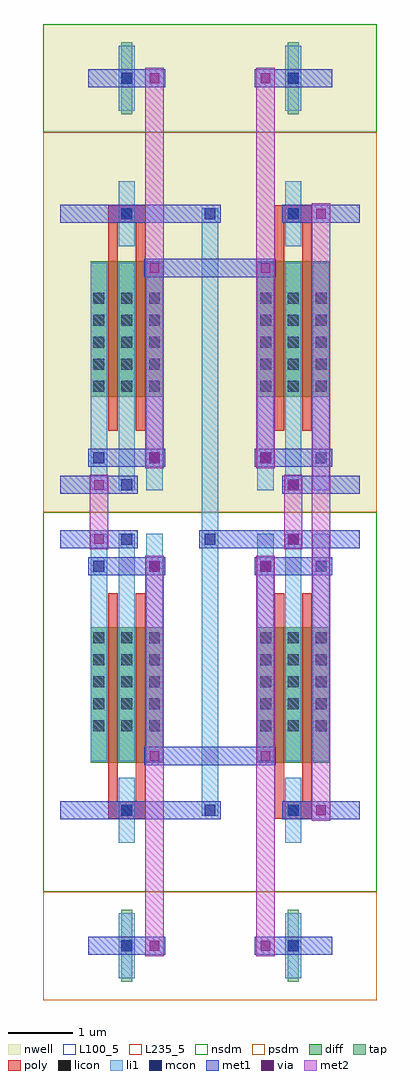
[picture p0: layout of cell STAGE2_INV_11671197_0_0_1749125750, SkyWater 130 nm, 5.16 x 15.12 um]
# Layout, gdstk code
from math import pi, radians
import gdstk
lib = gdstk.Library(unit=1e-6, precision=1e-09)
def R(c, l, rs):  # rectangles x0, y0, x1, y1
    for r in rs: c.add(gdstk.rectangle(r[:2], r[2:], *l))
def A(c, l, x, y, w, h, nx, ny, dx, dy):  # array of equal rectangles
    R(c, l, [(x+i*dx, y+j*dy, x+i*dx+w, y+j*dy+h) for i in range(nx) for j in range(ny)])
def P(c, l, *ps):  # polygons
    for p in ps: c.add(gdstk.Polygon(p, *l))
nwell = (64, 20)
diff = (65, 20)
tap = (65, 44)
poly = (66, 20)
licon = (66, 44)
li1 = (67, 20)
mcon = (67, 44)
met1 = (68, 20)
via = (68, 44)
met2 = (69, 20)
nsdm = (93, 44)
psdm = (94, 20)
L100_5 = (100, 5)
L235_5 = (235, 5)

nmos_s_72264633_x1_y1_17 = lib.new_cell('NMOS_S_72264633_X1_Y1_1749125749_1749125750')
R(nmos_s_72264633_x1_y1_17, diff, [(0.735,1.785,1.845,3.885)])
R(nmos_s_72264633_x1_y1_17, tap, [(1.205,6.16,1.375,7.28)])
R(nmos_s_72264633_x1_y1_17, poly, [(1,1.26,1.15,4.62), (1.43,1.26,1.58,4.62), (1,4.485,1.58,4.755)])
A(nmos_s_72264633_x1_y1_17, licon, 0.775, 1.865, 0.17, 0.17, 3, 5, 0.43, 0.34)
R(nmos_s_72264633_x1_y1_17, licon, [(1.205,4.535,1.375,4.705), (1.205,6.635,1.375,6.805)])
A(nmos_s_72264633_x1_y1_17, li1, 0.735, 0.335, 0.25, 3.53, 3, 1, 0.43, 0)
R(nmos_s_72264633_x1_y1_17, li1, [(1.165,4.115,1.415,5.125), (1.165,6.215,1.415,7.225)])
R(nmos_s_72264633_x1_y1_17, mcon, [(1.205,0.335,1.375,0.505), (0.775,0.755,0.945,0.925), (1.635,0.755,1.805,0.925), (1.205,4.535,1.375,4.705), (1.205,6.635,1.375,6.805)])
R(nmos_s_72264633_x1_y1_17, met1, [(0.26,0.28,1.46,0.56), (0.69,0.7,1.89,0.98), (0.26,4.48,1.46,4.76), (0.69,6.58,1.89,6.86)])
R(nmos_s_72264633_x1_y1_17, via, [(1.645,0.765,1.795,0.915), (1.645,6.645,1.795,6.795)])
R(nmos_s_72264633_x1_y1_17, met2, [(1.58,0.68,1.86,6.88)])
R(nmos_s_72264633_x1_y1_17, nsdm, [(0,0,2.58,5.88)])
R(nmos_s_72264633_x1_y1_17, psdm, [(0,5.88,2.58,7.56)])
R(nmos_s_72264633_x1_y1_17, L100_5, [(0,0,2.58,7.56)])

pmos_s_19745913_x1_y1_17 = lib.new_cell('PMOS_S_19745913_X1_Y1_1749125750_1749125750')
R(pmos_s_19745913_x1_y1_17, nwell, [(0,0,2.58,7.56)])
R(pmos_s_19745913_x1_y1_17, diff, [(0.735,1.785,1.845,3.885)])
R(pmos_s_19745913_x1_y1_17, tap, [(1.205,6.16,1.375,7.28)])
R(pmos_s_19745913_x1_y1_17, poly, [(1,1.26,1.15,4.62), (1.43,1.26,1.58,4.62), (1,4.485,1.58,4.755)])
A(pmos_s_19745913_x1_y1_17, licon, 0.775, 1.865, 0.17, 0.17, 3, 5, 0.43, 0.34)
R(pmos_s_19745913_x1_y1_17, licon, [(1.205,4.535,1.375,4.705), (1.205,6.635,1.375,6.805)])
A(pmos_s_19745913_x1_y1_17, li1, 0.735, 0.335, 0.25, 3.53, 3, 1, 0.43, 0)
R(pmos_s_19745913_x1_y1_17, li1, [(1.165,4.115,1.415,5.125), (1.165,6.215,1.415,7.225)])
R(pmos_s_19745913_x1_y1_17, mcon, [(1.205,0.335,1.375,0.505), (0.775,0.755,0.945,0.925), (1.635,0.755,1.805,0.925), (1.205,4.535,1.375,4.705), (1.205,6.635,1.375,6.805)])
R(pmos_s_19745913_x1_y1_17, met1, [(0.26,0.28,1.46,0.56), (0.69,0.7,1.89,0.98), (0.26,4.48,1.46,4.76), (0.69,6.58,1.89,6.86)])
R(pmos_s_19745913_x1_y1_17, via, [(1.645,0.765,1.795,0.915), (1.645,6.645,1.795,6.795)])
R(pmos_s_19745913_x1_y1_17, met2, [(1.58,0.68,1.86,6.88)])
R(pmos_s_19745913_x1_y1_17, nsdm, [(0,5.88,2.58,7.56)])
R(pmos_s_19745913_x1_y1_17, psdm, [(0,0,2.58,5.88)])
R(pmos_s_19745913_x1_y1_17, L100_5, [(0,0,2.58,7.56)])

stage2_inv_11671197_0_0_ = lib.new_cell('STAGE2_INV_11671197_0_0_1749125750')
R(stage2_inv_11671197_0_0_, li1, [(2.455,2.855,2.705,3.025), (2.455,2.855,2.705,3.025), (2.455,2.855,2.705,3.025), (2.455,2.855,2.705,3.025), (2.455,2.855,2.705,3.025), (2.455,2.855,2.705,3.025), (2.455,2.94,2.705,7.14), (2.455,7.055,2.705,7.225), (2.455,7.055,2.705,7.225), (2.455,7.055,2.705,7.225), (2.455,7.055,2.705,7.225), (2.455,7.055,2.705,7.225), (2.455,7.055,2.705,7.225), (2.455,7.14,2.705,12.18), (2.455,12.095,2.705,12.265), (2.455,12.095,2.705,12.265)])
R(stage2_inv_11671197_0_0_, mcon, [(2.495,2.855,2.665,3.025), (2.495,2.855,2.665,3.025), (2.495,2.855,2.665,3.025), (2.495,2.855,2.665,3.025), (2.495,2.855,2.665,3.025), (2.495,2.855,2.665,3.025), (2.495,7.055,2.665,7.225), (2.495,7.055,2.665,7.225), (2.495,7.055,2.665,7.225), (2.495,7.055,2.665,7.225), (2.495,7.055,2.665,7.225), (2.495,7.055,2.665,7.225), (2.495,12.095,2.665,12.265), (2.495,12.095,2.665,12.265)])
R(stage2_inv_11671197_0_0_, met1, [(1.29,2.8,2.58,3.08), (2.41,2.8,2.75,3.08), (2.41,2.8,2.75,3.08), (2.41,2.8,2.75,3.08), (2.41,2.8,2.75,3.08), (2.41,2.8,2.75,3.08), (2.41,2.8,2.75,3.08), (4.14,2.8,4.46,3.08), (4.14,2.8,4.46,3.08), (1.56,3.64,1.88,3.92), (1.56,3.64,1.88,3.92), (1.72,3.64,3.44,3.92), (3.28,3.64,3.6,3.92), (3.28,3.64,3.6,3.92), (0.7,7,1.02,7.28), (0.7,7,1.02,7.28), (2.41,7,2.75,7.28), (2.41,7,2.75,7.28), (2.41,7,2.75,7.28), (2.41,7,2.75,7.28), (2.41,7,2.75,7.28), (2.41,7,2.75,7.28), (2.58,7,3.87,7.28), (3.71,7,4.03,7.28), (3.71,7,4.03,7.28), (3.71,7,4.03,7.28), (3.71,7,4.03,7.28), (0.7,7.84,1.02,8.12), (0.7,7.84,1.02,8.12), (3.71,7.84,4.03,8.12), (3.71,7.84,4.03,8.12), (3.71,7.84,4.03,8.12), (3.71,7.84,4.03,8.12), (1.56,11.2,1.88,11.48), (1.56,11.2,1.88,11.48), (1.72,11.2,3.44,11.48), (3.28,11.2,3.6,11.48), (3.28,11.2,3.6,11.48), (1.29,12.04,2.58,12.32), (2.41,12.04,2.75,12.32), (2.41,12.04,2.75,12.32), (4.14,12.04,4.46,12.32), (4.14,12.04,4.46,12.32)])
P(stage2_inv_11671197_0_0_, met1, [(0,0),(0,0),(0,0),(0,0)],
  [(0,0),(0,0),(0,0),(0,0)],
  [(0,0),(0,0),(0,0),(0,0)],
  [(0,0),(0,0),(0,0),(0,0)],
  [(0,0),(0,0),(0,0),(0,0)],
  [(0,0),(0,0),(0,0),(0,0)],
  [(0,0),(0,0),(0,0),(0,0)],
  [(0,0),(0,0),(0,0),(0,0)])
R(stage2_inv_11671197_0_0_, via, [(4.225,2.865,4.375,3.015), (4.225,2.865,4.375,3.015), (1.645,3.705,1.795,3.855), (1.645,3.705,1.795,3.855), (3.365,3.705,3.515,3.855), (3.365,3.705,3.515,3.855), (0.785,7.065,0.935,7.215), (0.785,7.065,0.935,7.215), (3.795,7.065,3.945,7.215), (3.795,7.065,3.945,7.215), (3.795,7.065,3.945,7.215), (3.795,7.065,3.945,7.215), (0.785,7.905,0.935,8.055), (0.785,7.905,0.935,8.055), (3.795,7.905,3.945,8.055), (3.795,7.905,3.945,8.055), (3.795,7.905,3.945,8.055), (3.795,7.905,3.945,8.055), (1.645,11.265,1.795,11.415), (1.645,11.265,1.795,11.415), (3.365,11.265,3.515,11.415), (3.365,11.265,3.515,11.415), (4.225,12.105,4.375,12.255), (4.225,12.105,4.375,12.255)])
R(stage2_inv_11671197_0_0_, met2, [(4.16,2.78,4.44,3.1), (4.16,2.78,4.44,3.1), (4.16,2.94,4.44,12.18), (1.58,3.62,1.86,3.94), (1.58,3.62,1.86,3.94), (3.3,3.62,3.58,3.94), (3.3,3.62,3.58,3.94), (0.72,6.98,1,7.3), (0.72,6.98,1,7.3), (3.73,6.98,4.01,7.3), (3.73,6.98,4.01,7.3), (3.73,6.98,4.01,7.3), (3.73,6.98,4.01,7.3), (0.72,7.14,1,7.98), (3.73,7.14,4.01,7.98), (0.72,7.82,1,8.14), (0.72,7.82,1,8.14), (3.73,7.82,4.01,8.14), (3.73,7.82,4.01,8.14), (3.73,7.82,4.01,8.14), (3.73,7.82,4.01,8.14), (1.58,11.18,1.86,11.5), (1.58,11.18,1.86,11.5), (3.3,11.18,3.58,11.5), (3.3,11.18,3.58,11.5), (4.16,12.02,4.44,12.34), (4.16,12.02,4.44,12.34)])
P(stage2_inv_11671197_0_0_, met2, [(0,0),(0,0),(0,0),(0,0)],
  [(0,0),(0,0),(0,0),(0,0)],
  [(0,0),(0,0),(0,0),(0,0)],
  [(0,0),(0,0),(0,0),(0,0)])
R(stage2_inv_11671197_0_0_, L235_5, [(0,0,5.16,15.12)])
stage2_inv_11671197_0_0_.add(gdstk.Reference(nmos_s_72264633_x1_y1_17, (5.16,7.56), rotation=pi))
stage2_inv_11671197_0_0_.add(gdstk.Reference(nmos_s_72264633_x1_y1_17, (0,7.56), x_reflection=True))
stage2_inv_11671197_0_0_.add(gdstk.Reference(pmos_s_19745913_x1_y1_17, (5.16,7.56), rotation=pi, x_reflection=True))
stage2_inv_11671197_0_0_.add(gdstk.Reference(pmos_s_19745913_x1_y1_17, (0,7.56)))

lib.write_gds('STAGE2_INV_11671197_0_0_1749125750.gds')
